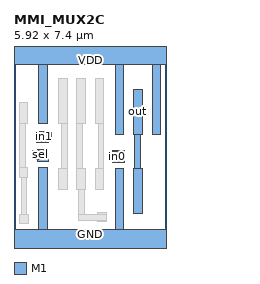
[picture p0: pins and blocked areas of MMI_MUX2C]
MACRO MMI_MUX2C
	CLASS CORE ;
	FOREIGN MMI_MUX2C 0 0 ;
	SIZE 5.92 BY 7.4 ;
	SYMMETRY X Y ;
	SITE CORE1 ;
	PIN out
		DIRECTION output ;
		USE SIGNAL ;
		PORT
			LAYER M1 ;
			RECT 4.655 4.19 4.995 5.95 ;
			LAYER M1 ;
			RECT 4.69 2.88 4.92 4.19 ;
			LAYER M1 ;
			RECT 4.655 1.12 4.995 2.88 ;
		END
		AntennaDiffArea 1.8768 ;
	END out
	PIN sel
		DIRECTION input ;
		USE SIGNAL ;
		PORT
			LAYER M1 ;
			RECT 0.905 3.57 1.355 3.59 ;
			LAYER M1 ;
			RECT 0.705 3.23 1.355 3.57 ;
			LAYER M1 ;
			RECT 0.905 3.14 1.355 3.23 ;
		END
		AntennaGateArea 0.7452 ;
	END sel
	PIN in1
		DIRECTION input ;
		USE SIGNAL ;
		PORT
			LAYER M1 ;
			RECT 0.89 4.265 1.34 4.315 ;
			LAYER M1 ;
			RECT 0.89 3.925 1.46 4.265 ;
			LAYER M1 ;
			RECT 0.89 3.865 1.34 3.925 ;
		END
		AntennaGateArea 0.495 ;
	END in1
	PIN GND
		DIRECTION inout ;
		USE GROUND ;
		PORT
			LAYER M1 ;
			RECT 0.965 0.5 1.305 2.91 ;
			LAYER M1 ;
			RECT 3.935 0.5 4.275 2.88 ;
			LAYER M1 ;
			RECT 0 -0.5 5.92 0.5 ;
		END
	END GND
	PIN VDD
		DIRECTION inout ;
		USE POWER ;
		PORT
			LAYER M1 ;
			RECT 0 6.9 5.92 7.9 ;
			LAYER M1 ;
			RECT 0.965 4.6 1.305 6.9 ;
			LAYER M1 ;
			RECT 3.935 4.19 4.275 6.9 ;
			LAYER M1 ;
			RECT 5.375 4.19 5.715 6.9 ;
		END
	END VDD
	PIN in0
		DIRECTION input ;
		USE SIGNAL ;
		PORT
			LAYER M1 ;
			RECT 3.845 3.51 4.295 3.565 ;
			LAYER M1 ;
			RECT 3.74 3.17 4.295 3.51 ;
			LAYER M1 ;
			RECT 3.845 3.115 4.295 3.17 ;
		END
		AntennaGateArea 0.4968 ;
	END in0
	OBS
		LAYER M1 ;
		RECT 0.205 4.6 0.545 5.44 ;
		LAYER M1 ;
		RECT 1.725 4.6 2.065 6.36 ;
		LAYER M1 ;
		RECT 0.21 2.91 0.44 4.6 ;
		LAYER M1 ;
		RECT 0.205 2.53 0.545 2.91 ;
		LAYER M1 ;
		RECT 0.275 1.07 0.505 2.53 ;
		LAYER M1 ;
		RECT 0.225 0.73 0.565 1.07 ;
		LAYER M1 ;
		RECT 1.835 2.88 2.065 4.6 ;
		LAYER M1 ;
		RECT 1.725 2.04 2.065 2.88 ;
		LAYER M1 ;
		RECT 2.445 4.6 2.785 6.36 ;
		LAYER M1 ;
		RECT 3.165 4.6 3.505 6.36 ;
		LAYER M1 ;
		RECT 2.445 2.88 2.675 4.6 ;
		LAYER M1 ;
		RECT 3.275 2.88 3.505 4.6 ;
		LAYER M1 ;
		RECT 2.445 2.04 2.785 2.88 ;
		LAYER M1 ;
		RECT 3.165 2.04 3.505 2.88 ;
		LAYER M1 ;
		RECT 2.505 1.07 2.735 2.04 ;
		LAYER M1 ;
		RECT 3.245 1.07 3.585 1.135 ;
		LAYER M1 ;
		RECT 2.505 0.84 3.585 1.07 ;
		LAYER M1 ;
		RECT 3.245 0.795 3.585 0.84 ;
	END
END MMI_MUX2C
